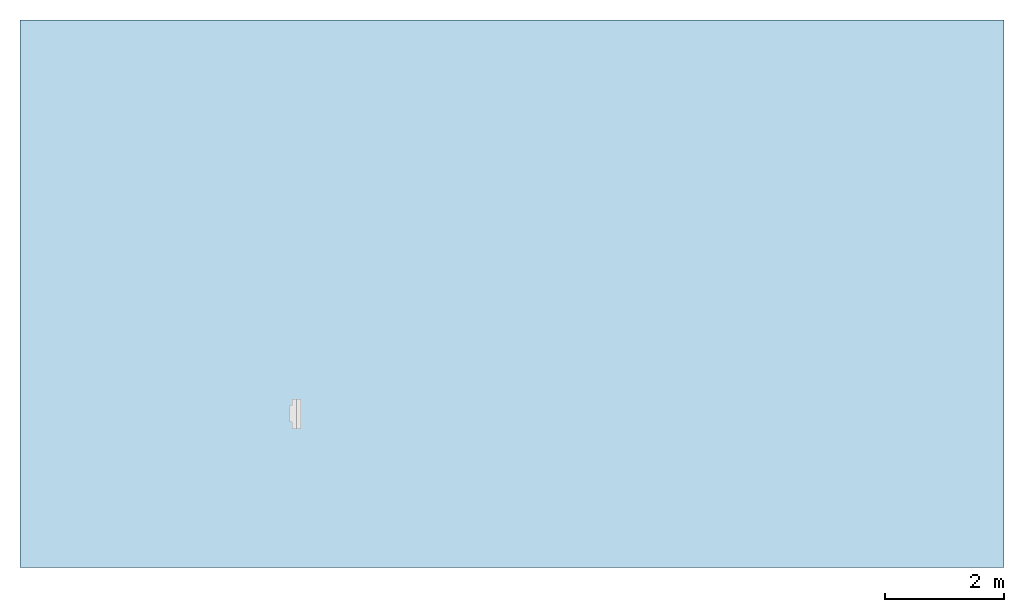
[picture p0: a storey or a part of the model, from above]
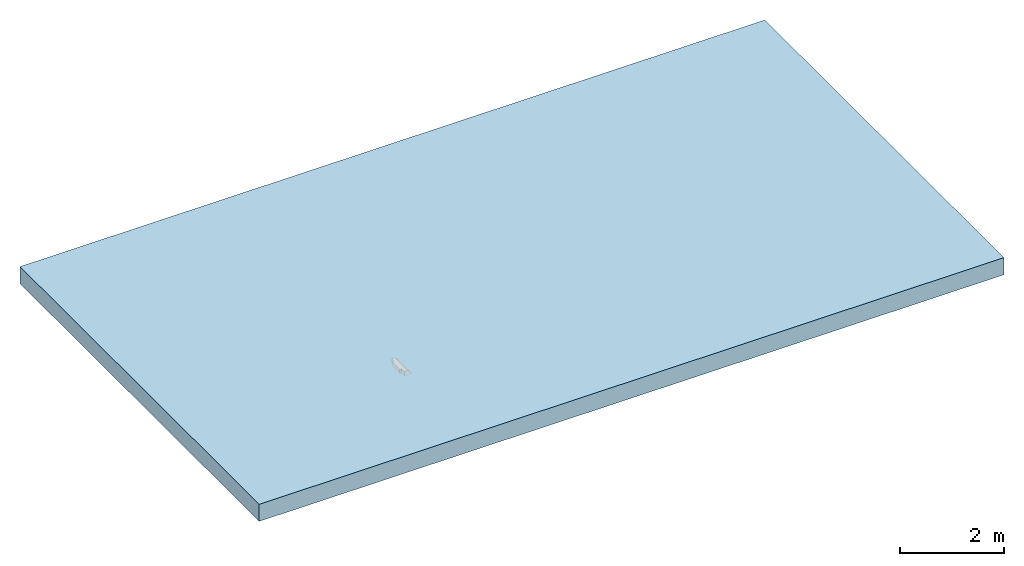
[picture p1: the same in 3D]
Properties of the parts of a building model (IFC2X3)

# File
Description: ViewDefinition [CoordinationView]
File name: 4242 - Access Unit - 500mm LG.ifc
Time: 2013-09-02T12:19:28
Written by: Autodesk Revit 2013
Made in: 20120221_2030(x64)

# IfcProject, Project Number
LongName: Project Name; Phase: Project Status

# IfcSite, Default
RefLatitude: 42, 21, 30, 344238; RefLongitude: -71, -3, -35, -194702; RefElevation: 0 mm

# IfcBuilding
Pset_BuildingCommon - NumberOfStoreys: 1
Other - Project Name: Project Name; Project Number: Project Number; Project Address: ## Street City, State Zip; Client Name: Owner; Project Status: Project Status; Project Issue Date: Issue Date

# IfcBuildingStorey, Level 1
LongName: Level 1; Elevation: 0 mm
Constraints - Elevation Base: 0; Elevation: 0 mm
Graphics - Line Pattern: Center; Line Weight: 1; Color: 0; Symbol: M_Level Head - Circle: M_Level Head - Circle; Symbol at End 1 Default: no; Symbol at End 2 Default: yes
Identity Data - Name: Level 1; Structural: no; Building Story: yes
Dimensions - Computation Height: 0 mm

# IfcBuildingElementProxy: 4242 - Access Unit - 500mm LG, Civil-Drainage-Channel-ACO-KerbDrain-SP380:4242 - Access Unit - 500mm LG:4242 - Access Unit - 500mm LG:308659
In: Level 1
Material: ACO Polymer Concrete., Iron, Cast
Dimensions - Volume: 18654160 mm3; Endcap void: 2000 mm; Access hole: -41.54 mm; AccessDepth: 126 mm; Void Width: 150 mm; Void Length: 500 mm; Void Depth: -280 mm
Constraints - Moves With Nearby Elements: no; Level: Level: Level 1
Phasing - Phase Created: New Construction
Pset_BuildingElementProxyCommon - Reference: 4242 - Access Unit - 500mm LG
Data - Channel C.S.A: 0.03m²; Load Class: A 15 - D 400; Invert Depth: 355mm; Drainage Slot Width: N/A; ACO Hydraulic Design Software: http://www.acodesign.co.uk; Product Standard: BS EN 1433:2002, CE marked, Kitemarked; Product Weight: 36.1 Kg; Hydraulic Performance: http://www.aco.co.uk/download.php?id=120; Concrete Surround Volume - Load Class A 15 - D 400 - Concrete Pavement: 0.17m³/m; Installation - Concrete Grade: Refer to brochure; Connection Pipe O.D: N/A; Drainage Slot Intake area: N/A; Product Dimensions: 500mm x 150mm x 380mm (LxWxH); Concrete Surround Volume - Load Class A 15 - D 400 - Grass or Asphalt Pavement: 0.15m³/m
Other - CreatedBy: www.aco.co.uk; Revision: 1
Identity Data - Fax: +44 (0)1462 815895; Maintenance guidelines: http://www.aco.co.uk/download.php?id=120; Telephone: +44 (0)1462 816666; Product Code: 4242; Assembly Description: Rain Water Drainage; Type Comments: ACO KerbDrain SP380 splayed access unit 500mm long; e-mail Sales: customersupport@aco.co.uk; Model: ACO KerbDrain SP380; e-mail Technical: technical@aco.co.uk; OmniClass Title: Rainwater Removal; Manufacturer: ACO Technologies plc - ACO Water Management Division; Product brochure: http://www.aco.co.uk/download.php?id=120; Model Description: Combined kerb and drainage system; Price: POA - contact ACO; Address: ACO Business Park, Hitchin Road, Shefford, Bedfordshire, United Kingdom SG17 5TE; OmniClass Number: 23.70.50.24; Cost: 0; Assembly Code: D2040; Installation guidelines: http://www.aco.co.uk/download.php?id=120; Product Page URL: http://www.aco.co.uk/product_detail.php?id=3; URL: www.aco.co.uk
Materials and Finishes - Access Cover/Frame Colour: Black; Channel Colour: Grey; Connection Pipe Material Colour: N/A; End Cap Material: N/A; Channel Material: Vienite® Synthetic Resin Concrete; Access Cover/Frame Material: Ductile Iron; Connection Pipe Material: N/A; End Cap Colour: N/A; Access Cover/Frame Finish: Water Based Paint Coating
Construction - RH transition unit: no; SP380-500: no; RH drop kerb: no; Centre Stone: no; Closing end cap: no; SP380 - 1000: no; LH inlet/outlet end cap: no; RH inlet/outlet end cap: no; LH drop kerb: no; Access Unit: yes; LH transition unit: no
General - TagNumber: 0.000000; SerialNumber: 0.000000
Green Building Properties - End Cap Recycled Material Content: N/A; Access Cover/Frame Recyclable: Fully recyclable; Access Cover/Frame Recycled Material Content: Between 40% - 90%; End Cap Recyclable: N/A; Channel Recycled Material Content: 20% minimum; Channel Recyclable: Fully recyclable

# IfcOpeningElement: Recess (2)
In: Level 1
Dimensions - Volume: 60563750825 mm3; Perimeter: 51360 mm; Area: 151470000 mm2; Thickness: 400 mm
Constraints - Room Bounding: yes; Related to Mass: no; Level: Level: Level 1; Height Offset From Level: 0 mm
Phasing - Phase Created: New Construction
Structural - Enable Analytical Model: no; Structural: no
Graphics - Coarse Scale Fill Color: 0
Analytical Properties - Roughness: 1; Absorptance: 0.1
Construction - Function: 0; Default Thickness: 400 mm
Materials and Finishes - Structural Material: Plant

# IfcSlab: Floor:Generic Floor - 400mm, Floor:Generic Floor - 400mm:193825
In: Level 1
PredefinedType: FLOOR; Material: Plant 400 mm
Dimensions - Volume: 60563750825 mm3; Perimeter: 51360 mm; Area: 151470000 mm2; Thickness: 400 mm
Constraints - Room Bounding: yes; Related to Mass: no; Level: Level: Level 1; Height Offset From Level: 0 mm
Phasing - Phase Created: New Construction
Structural - Enable Analytical Model: no; Structural: no
Pset_SlabCommon - Reference: Generic Floor - 400mm; IsExternal: no; LoadBearing: yes
Graphics - Coarse Scale Fill Color: 0
Analytical Properties - Roughness: 1; Absorptance: 0.1
Construction - Function: 0; Default Thickness: 400 mm
Materials and Finishes - Structural Material: Plant
